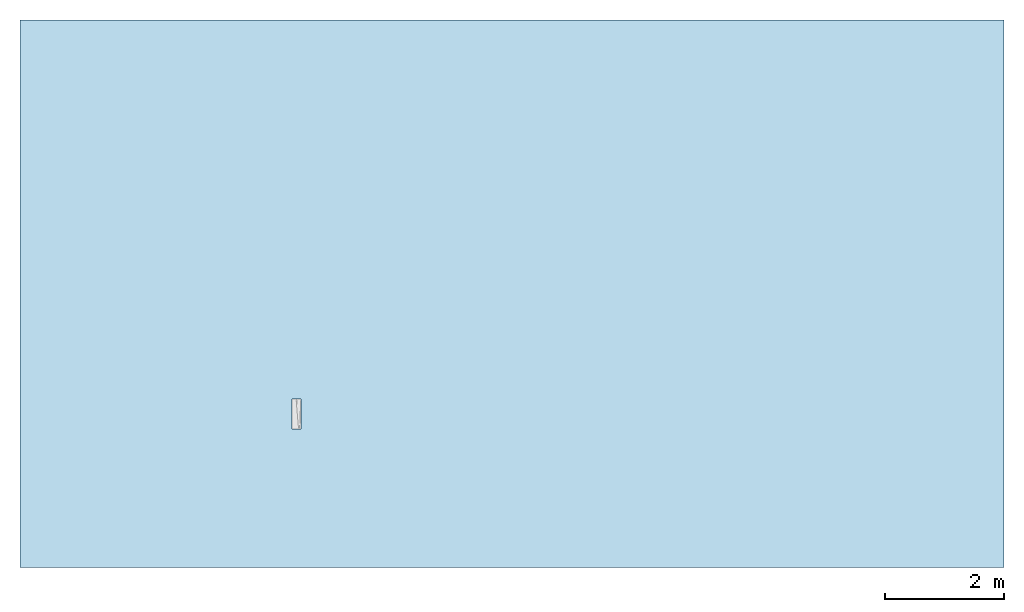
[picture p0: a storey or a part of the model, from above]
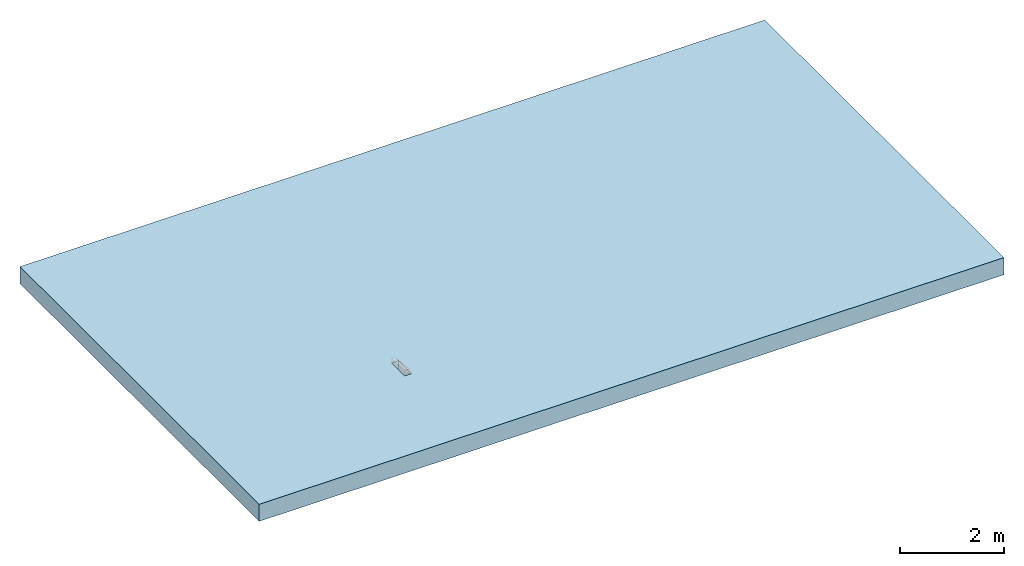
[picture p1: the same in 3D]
Properties of the parts of a building model (IFC2X3)

# File
Description: ViewDefinition [CoordinationView]
File name: 4245 - LH transition kerb - 500mm LG.ifc
Time: 2013-09-02T12:23:28
Written by: Autodesk Revit 2013
Made in: 20120221_2030(x64)

# IfcProject, Project Number
LongName: Project Name; Phase: Project Status

# IfcSite, Default
RefLatitude: 42, 21, 30, 344238; RefLongitude: -71, -3, -35, -194702; RefElevation: 0 mm

# IfcBuilding
Pset_BuildingCommon - NumberOfStoreys: 1
Other - Project Status: Project Status; Project Address: ## Street City, State Zip; Client Name: Owner; Project Number: Project Number; Project Name: Project Name; Project Issue Date: Issue Date

# IfcBuildingStorey, Level 1
LongName: Level 1; Elevation: 0 mm
Constraints - Elevation Base: 0; Elevation: 0 mm
Graphics - Symbol: M_Level Head - Circle: M_Level Head - Circle; Color: 0; Line Weight: 1; Symbol at End 2 Default: yes; Line Pattern: Center; Symbol at End 1 Default: no
Identity Data - Structural: no; Building Story: yes; Name: Level 1
Dimensions - Computation Height: 0 mm

# IfcBuildingElementProxy: 4245 - LH transition kerb - 500mm LG, Civil-Drainage-Channel-ACO-KerbDrain-SP380:4245 - LH transition kerb - 500mm LG:4245 - LH transition kerb - 500mm LG:308659
In: Level 1
Material: ACO Polymer Concrete.
Dimensions - Volume: 15193249 mm3; AccessDepth: 2000 mm; Void Width: 150 mm; Void Depth: -280 mm; Access hole: 20 mm; Void Length: 500 mm; Endcap void: 2000 mm
Phasing - Phase Created: New Construction
Constraints - Moves With Nearby Elements: no; Level: Level: Level 1
Pset_BuildingElementProxyCommon - Reference: 4245 - LH transition kerb - 500mm LG
General - TagNumber: 0.000000; SerialNumber: 0.000000
Data - Product Dimensions: 500mm x 150mm x 405/380mm (LxWxH); ACO Hydraulic Design Software: http://www.acodesign.co.uk; Invert Depth: 380/355mm; Drainage Slot Width: N/A; Drainage Slot Intake area: N/A; Installation - Concrete Grade: Refer to brochure; Product Weight: 31 Kg; Channel C.S.A: 0.03mm²; Product Standard: BS EN 1433:2002, CE marked, Kitemarked; Concrete Surround Volume - Load Class A 15 - D 400 - Concrete Pavement: N/A; Hydraulic Performance: http://www.aco.co.uk/download.php?id=120; Concrete Surround Volume - Load Class A 15 - D 400 - Grass or Asphalt Pavement: N/A; Connection Pipe O.D: N/A; Load Class: A 15 - D 400
Green Building Properties - End Cap Recycled Material Content: N/A; Channel Recycled Material Content: 20% minimum; Access Cover/Frame Recyclable: N/A; Channel Recyclable: Fully recyclable; End Cap Recyclable: N/A; Access Cover/Frame Recycled Material Content: N/A
Identity Data - Installation guidelines: http://www.aco.co.uk/download.php?id=120; Assembly Description: Rain Water Drainage; Price: POA - contact ACO; e-mail Sales: customersupport@aco.co.uk; Product Code: 4245; Address: ACO Business Park, Hitchin Road, Shefford, Bedfordshire, United Kingdom SG17 5TE; e-mail Technical: technical@aco.co.uk; Fax: +44 (0)1462 815895; Model Description: Combined kerb and drainage system; Telephone: +44 (0)1462 816666; Model: ACO KerbDrain SP380; Manufacturer: ACO Technologies plc - ACO Water Management Division; URL: www.aco.co.uk; Assembly Code: D2040; Type Comments: ACO KerbDrain SP380 splayed LH transition unit 500mm long; Product Page URL: http://www.aco.co.uk/product_detail.php?id=3; OmniClass Title: Rainwater Removal; Cost: 0; Product brochure: http://www.aco.co.uk/download.php?id=120; OmniClass Number: 23.70.50.24; Maintenance guidelines: http://www.aco.co.uk/download.php?id=120
Construction - SP380 - 1000: no; Centre Stone: no; SP380-500: no; RH transition unit: no; Access Unit: no; LH transition unit: yes; Closing end cap: no; RH inlet/outlet end cap: no; LH drop kerb: no; RH drop kerb: no; LH inlet/outlet end cap: no
Materials and Finishes - Access Cover/Frame Material: N/A; Connection Pipe Material: N/A; Access Cover/Frame Colour: N/A; End Cap Material: N/A; Channel Material: Vienite® Synthetic Resin Concrete; End Cap Colour: N/A; Connection Pipe Material Colour: N/A; Channel Colour: Grey; Access Cover/Frame Finish: N/A
Other - CreatedBy: www.aco.co.uk; Revision: 1

# IfcOpeningElement: Recess (3)
In: Level 1
Constraints - Room Bounding: yes; Height Offset From Level: 0 mm; Related to Mass: no; Level: Level: Level 1
Dimensions - Area: 151470000 mm2; Perimeter: 51360 mm; Volume: 60567000000 mm3; Thickness: 400 mm
Phasing - Phase Created: New Construction
Structural - Enable Analytical Model: no; Structural: no
Analytical Properties - Roughness: 1; Absorptance: 0.1
Graphics - Coarse Scale Fill Color: 0
Construction - Default Thickness: 400 mm; Function: 0
Materials and Finishes - Structural Material: Plant

# IfcSlab: Floor:Generic Floor - 400mm, Floor:Generic Floor - 400mm:193825
In: Level 1
PredefinedType: FLOOR; Material: Plant 400 mm
Constraints - Room Bounding: yes; Height Offset From Level: 0 mm; Related to Mass: no; Level: Level: Level 1
Dimensions - Area: 151470000 mm2; Perimeter: 51360 mm; Volume: 60567000000 mm3; Thickness: 400 mm
Phasing - Phase Created: New Construction
Structural - Enable Analytical Model: no; Structural: no
Pset_SlabCommon - Reference: Generic Floor - 400mm; IsExternal: no; LoadBearing: yes
Analytical Properties - Roughness: 1; Absorptance: 0.1
Graphics - Coarse Scale Fill Color: 0
Construction - Default Thickness: 400 mm; Function: 0
Materials and Finishes - Structural Material: Plant
